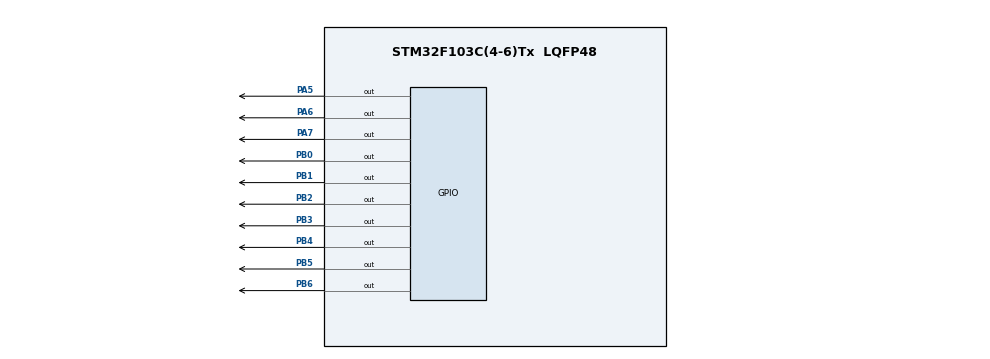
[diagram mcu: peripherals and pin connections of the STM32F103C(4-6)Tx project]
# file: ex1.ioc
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Mcu.Family=STM32F1
Mcu.Name=STM32F103C(4-6)Tx
Mcu.Package=LQFP48
NVIC.PriorityGroup=NVIC_PRIORITYGROUP_4
NVIC.TIM2_IRQn=true\:0\:0\:false\:false\:true\:true\:true
PA5.Signal=GPIO_Output
PA6.Signal=GPIO_Output
PA7.Signal=GPIO_Output
PB0.Signal=GPIO_Output
PB1.Signal=GPIO_Output
PB2.Signal=GPIO_Output
PB3.Signal=GPIO_Output
PB4.Signal=GPIO_Output
PB5.Signal=GPIO_Output
PB6.Signal=GPIO_Output
PD0-OSC_IN.Mode=HSE-External-Oscillator
PD0-OSC_IN.Signal=RCC_OSC_IN
PD1-OSC_OUT.Mode=HSE-External-Oscillator
PD1-OSC_OUT.Signal=RCC_OSC_OUT
ProjectManager.HeapSize=0x200
ProjectManager.StackSize=0x400
ProjectManager.TargetToolchain=STM32CubeIDE
RCC.APB1Freq_Value=8000000
RCC.APB2Freq_Value=8000000
TIM2.Period=9
TIM2.Prescaler=7999
VP_SYS_VS_ND.Mode=No_Debug
VP_TIM2_VS_ClockSourceINT.Mode=Internal
board=custom

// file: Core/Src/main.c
/* USER CODE BEGIN Header */
/**
  ******************************************************************************
  * @file           : main.c
  * @brief          : Main program body
  ******************************************************************************
  * @attention
  *
  * <h2><center>&copy; Copyright (c) 2021 STMicroelectronics.
  * All rights reserved.</center></h2>
  *
  * This software component is licensed by ST under BSD 3-Clause license,
  * the "License"; You may not use this file except in compliance with the
  * License. You may obtain a copy of the License at:
  *                        opensource.org/licenses/BSD-3-Clause
  *
  ******************************************************************************
  */
/* USER CODE END Header */
#include "main.h"

TIM_HandleTypeDef htim2;

void SystemClock_Config(void);
static void MX_GPIO_Init(void);
static void MX_TIM2_Init(void);

/* USER CODE BEGIN 0 */
void display7SEG(int);
int led_buffer[4] = {2, 1, 5, 9};
/* USER CODE END 0 */

int main(void)
{

  /* MCU Configuration--------------------------------------------------------*/

  /* Reset of all peripherals, Initializes the Flash interface and the Systick. */
  HAL_Init();

  /* Configure the system clock */
  SystemClock_Config();

  /* Initialize all configured peripherals */
  MX_GPIO_Init();
  MX_TIM2_Init();
  /* USER CODE BEGIN 2 */
  HAL_TIM_Base_Start_IT(&htim2);
//  HAL_GPIO_TogglePin(GPIOA, GPIO_PIN_6);
  HAL_GPIO_TogglePin(GPIOA, GPIO_PIN_7);
//  HAL_GPIO_TogglePin(GPIOA, GPIO_PIN_8);
//  HAL_GPIO_TogglePin(GPIOA, GPIO_PIN_9);
  display7SEG(1);
  /* USER CODE END 2 */

  /* Infinite loop */
  /* USER CODE BEGIN WHILE */
//  int hour = 15, minute = 8, second = 50;
//  void updateClockBuffer() {
//  	led_buffer[0] = hour / 10;
//  	led_buffer[1] = hour % 10;
//  	led_buffer[2] = minute / 10;
//  	led_buffer[3] = minute % 10;
//  }
  while (1)
  {
    /* USER CODE END WHILE */

  }
}

void SystemClock_Config(void)
{
  RCC_OscInitTypeDef RCC_OscInitStruct = {0};
  RCC_ClkInitTypeDef RCC_ClkInitStruct = {0};

  /** Initializes the RCC Oscillators according to the specified parameters
  * in the RCC_OscInitTypeDef structure.
  */
  RCC_OscInitStruct.OscillatorType = RCC_OSCILLATORTYPE_HSI;
  RCC_OscInitStruct.HSIState = RCC_HSI_ON;
  RCC_OscInitStruct.HSICalibrationValue = RCC_HSICALIBRATION_DEFAULT;
  RCC_OscInitStruct.PLL.PLLState = RCC_PLL_NONE;
  if (HAL_RCC_OscConfig(&RCC_OscInitStruct) != HAL_OK)
  {
    Error_Handler();
  }
  /** Initializes the CPU, AHB and APB buses clocks
  */
  RCC_ClkInitStruct.ClockType = RCC_CLOCKTYPE_HCLK|RCC_CLOCKTYPE_SYSCLK
                              |RCC_CLOCKTYPE_PCLK1|RCC_CLOCKTYPE_PCLK2;
  RCC_ClkInitStruct.SYSCLKSource = RCC_SYSCLKSOURCE_HSI;
  RCC_ClkInitStruct.AHBCLKDivider = RCC_SYSCLK_DIV1;
  RCC_ClkInitStruct.APB1CLKDivider = RCC_HCLK_DIV1;
  RCC_ClkInitStruct.APB2CLKDivider = RCC_HCLK_DIV1;

  if (HAL_RCC_ClockConfig(&RCC_ClkInitStruct, FLASH_LATENCY_0) != HAL_OK)
  {
    Error_Handler();
  }
}

static void MX_TIM2_Init(void)
{

  TIM_ClockConfigTypeDef sClockSourceConfig = {0};
  TIM_MasterConfigTypeDef sMasterConfig = {0};

  htim2.Instance = TIM2;
  htim2.Init.Prescaler = 7999;
  htim2.Init.CounterMode = TIM_COUNTERMODE_UP;
  htim2.Init.Period = 9;
  htim2.Init.ClockDivision = TIM_CLOCKDIVISION_DIV1;
  htim2.Init.AutoReloadPreload = TIM_AUTORELOAD_PRELOAD_DISABLE;
  if (HAL_TIM_Base_Init(&htim2) != HAL_OK)
  {
    Error_Handler();
  }
  sClockSourceConfig.ClockSource = TIM_CLOCKSOURCE_INTERNAL;
  if (HAL_TIM_ConfigClockSource(&htim2, &sClockSourceConfig) != HAL_OK)
  {
    Error_Handler();
  }
  sMasterConfig.MasterOutputTrigger = TIM_TRGO_RESET;
  sMasterConfig.MasterSlaveMode = TIM_MASTERSLAVEMODE_DISABLE;
  if (HAL_TIMEx_MasterConfigSynchronization(&htim2, &sMasterConfig) != HAL_OK)
  {
    Error_Handler();
  }

}

static void MX_GPIO_Init(void)
{
  GPIO_InitTypeDef GPIO_InitStruct = {0};

  /* GPIO Ports Clock Enable */
  __HAL_RCC_GPIOD_CLK_ENABLE();
  __HAL_RCC_GPIOA_CLK_ENABLE();
  __HAL_RCC_GPIOB_CLK_ENABLE();

  /*Configure GPIO pin Output Level */
  HAL_GPIO_WritePin(GPIOA, GPIO_PIN_4|GPIO_PIN_5|GPIO_PIN_6|GPIO_PIN_7
                          |GPIO_PIN_8|GPIO_PIN_9, GPIO_PIN_RESET);

  /*Configure GPIO pin Output Level */
  HAL_GPIO_WritePin(GPIOB, GPIO_PIN_0|GPIO_PIN_1|GPIO_PIN_2|GPIO_PIN_3
                          |GPIO_PIN_4|GPIO_PIN_5|GPIO_PIN_6, GPIO_PIN_RESET);

  /*Configure GPIO pins : PA4 PA5 PA6 PA7
                           PA8 PA9 */
  GPIO_InitStruct.Pin = GPIO_PIN_4|GPIO_PIN_5|GPIO_PIN_6|GPIO_PIN_7
                          |GPIO_PIN_8|GPIO_PIN_9;
  GPIO_InitStruct.Mode = GPIO_MODE_OUTPUT_PP;
  GPIO_InitStruct.Pull = GPIO_NOPULL;
  GPIO_InitStruct.Speed = GPIO_SPEED_FREQ_LOW;
  HAL_GPIO_Init(GPIOA, &GPIO_InitStruct);

  /*Configure GPIO pins : PB0 PB1 PB2 PB3
                           PB4 PB5 PB6 */
  GPIO_InitStruct.Pin = GPIO_PIN_0|GPIO_PIN_1|GPIO_PIN_2|GPIO_PIN_3
                          |GPIO_PIN_4|GPIO_PIN_5|GPIO_PIN_6;
  GPIO_InitStruct.Mode = GPIO_MODE_OUTPUT_PP;
  GPIO_InitStruct.Pull = GPIO_NOPULL;
  GPIO_InitStruct.Speed = GPIO_SPEED_FREQ_LOW;
  HAL_GPIO_Init(GPIOB, &GPIO_InitStruct);

}

/* USER CODE BEGIN 4 */
void display7SEG(int num) {
	HAL_GPIO_WritePin(GPIOB, GPIO_PIN_0|GPIO_PIN_1|GPIO_PIN_2|GPIO_PIN_3|GPIO_PIN_4|GPIO_PIN_5|GPIO_PIN_6, GPIO_PIN_SET);
	switch (num) {
		case 0:
			HAL_GPIO_WritePin(GPIOB, GPIO_PIN_0|GPIO_PIN_1|GPIO_PIN_2|GPIO_PIN_3|GPIO_PIN_4|GPIO_PIN_5, GPIO_PIN_RESET);
			break;
		case 1:
			HAL_GPIO_WritePin(GPIOB, GPIO_PIN_1|GPIO_PIN_2, GPIO_PIN_RESET);
			break;
		case 2:
			HAL_GPIO_WritePin(GPIOB, GPIO_PIN_0|GPIO_PIN_1|GPIO_PIN_3|GPIO_PIN_4|GPIO_PIN_6, GPIO_PIN_RESET);
			break;
		case 3:
			HAL_GPIO_WritePin(GPIOB, GPIO_PIN_0|GPIO_PIN_1|GPIO_PIN_2|GPIO_PIN_3|GPIO_PIN_6, GPIO_PIN_RESET);
			break;
		case 4:
			HAL_GPIO_WritePin(GPIOB, GPIO_PIN_1|GPIO_PIN_2|GPIO_PIN_5|GPIO_PIN_6, GPIO_PIN_RESET);
			break;
		case 5:
			HAL_GPIO_WritePin(GPIOB, GPIO_PIN_0|GPIO_PIN_2|GPIO_PIN_3|GPIO_PIN_5|GPIO_PIN_6, GPIO_PIN_RESET);
			break;
		case 6:
			HAL_GPIO_WritePin(GPIOB, GPIO_PIN_0|GPIO_PIN_2|GPIO_PIN_3|GPIO_PIN_4|GPIO_PIN_5|GPIO_PIN_6, GPIO_PIN_RESET);
			break;
		case 7:
			HAL_GPIO_WritePin(GPIOB, GPIO_PIN_0|GPIO_PIN_1|GPIO_PIN_2, GPIO_PIN_RESET);
			break;
		case 8:
			HAL_GPIO_WritePin(GPIOB, GPIO_PIN_0|GPIO_PIN_1|GPIO_PIN_2|GPIO_PIN_3|GPIO_PIN_4|GPIO_PIN_5|GPIO_PIN_6, GPIO_PIN_RESET);
			break;
		case 9:
			HAL_GPIO_WritePin(GPIOB, GPIO_PIN_0|GPIO_PIN_1|GPIO_PIN_2|GPIO_PIN_3|GPIO_PIN_5|GPIO_PIN_6, GPIO_PIN_RESET);
			break;
		default:
			break;
	}
}

const int MAX_LED = 4;
int index_led = 0;
//led_buffer[4] = {2, 1, 5, 9};
void update7SEG(int index) {
	switch (index) {
	case 0:
		if (HAL_GPIO_ReadPin(GPIOA, GPIO_PIN_9) == GPIO_PIN_RESET){
			HAL_GPIO_TogglePin(GPIOA, GPIO_PIN_9);
		}
		HAL_GPIO_TogglePin(GPIOA, GPIO_PIN_6);
		display7SEG(led_buffer[0]);
		break;
	case 1:
		HAL_GPIO_TogglePin(GPIOA, GPIO_PIN_6);
		HAL_GPIO_TogglePin(GPIOA, GPIO_PIN_7);
		display7SEG(led_buffer[1]);
		break;
	case 2:
		HAL_GPIO_TogglePin(GPIOA, GPIO_PIN_7);
		HAL_GPIO_TogglePin(GPIOA, GPIO_PIN_8);
		display7SEG(led_buffer[2]);
		break;
	case 3:
		HAL_GPIO_TogglePin(GPIOA, GPIO_PIN_8);
		HAL_GPIO_TogglePin(GPIOA, GPIO_PIN_9);
		display7SEG(led_buffer[3]);
		break;
	default:
		break;
	}
}

int counter = 50;
int i = 0;
void HAL_TIM_PeriodElapsedCallback(TIM_HandleTypeDef *htim) {
	counter--;
	if (counter <= 0 && i == 0) {
		counter = 50;
		HAL_GPIO_TogglePin(GPIOA, GPIO_PIN_6);
		HAL_GPIO_TogglePin(GPIOA, GPIO_PIN_7);
		display7SEG(9);
		i = 1;
	}
	if (counter <= 0 && i == 1) {
		counter = 50;
		HAL_GPIO_TogglePin(GPIOA, GPIO_PIN_7);
		HAL_GPIO_TogglePin(GPIOA, GPIO_PIN_6);
		display7SEG(6);
		i = 0;
	}
}
/* USER CODE END 4 */

void Error_Handler(void)
{
  __disable_irq();
  while (1)
  {
  }
}

/************************ (C) COPYRIGHT STMicroelectronics *****END OF FILE****/
